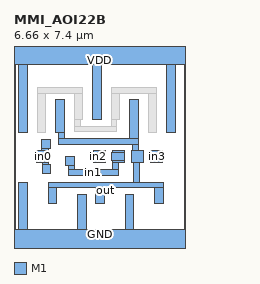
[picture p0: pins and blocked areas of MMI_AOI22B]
MACRO MMI_AOI22B
	CLASS CORE ;
	FOREIGN MMI_AOI22B 0 0 ;
	SIZE 6.66 BY 7.4 ;
	SYMMETRY X Y ;
	SITE CORE1 ;
	PIN out
		DIRECTION output ;
		USE SIGNAL ;
		PORT
			LAYER M1 ;
			RECT 1.62 4.275 1.96 5.555 ;
			LAYER M1 ;
			RECT 1.73 4.025 1.96 4.275 ;
			LAYER M1 ;
			RECT 4.5 4.025 4.84 5.555 ;
			LAYER M1 ;
			RECT 1.73 3.795 4.84 4.025 ;
			LAYER M1 ;
			RECT 4.61 3.555 4.84 3.795 ;
			LAYER M1 ;
			RECT 4.585 3.105 5.035 3.555 ;
			LAYER M1 ;
			RECT 4.655 2.335 4.885 3.105 ;
			LAYER M1 ;
			RECT 1.33 2.105 5.82 2.335 ;
			LAYER M1 ;
			RECT 1.33 1.495 1.67 2.105 ;
			LAYER M1 ;
			RECT 3.18 1.495 3.52 2.105 ;
			LAYER M1 ;
			RECT 5.48 1.495 5.82 2.105 ;
		END
		AntennaDiffArea 3.3672 ;
	END out
	PIN in1
		DIRECTION input ;
		USE SIGNAL ;
		PORT
			LAYER M1 ;
			RECT 3.845 3.5 4.295 3.555 ;
			LAYER M1 ;
			RECT 2 2.995 2.34 3.335 ;
			LAYER M1 ;
			RECT 3.785 3.16 4.295 3.5 ;
			LAYER M1 ;
			RECT 2.11 2.815 2.34 2.995 ;
			LAYER M1 ;
			RECT 3.835 3.105 4.295 3.16 ;
			LAYER M1 ;
			RECT 3.835 2.815 4.065 3.105 ;
			LAYER M1 ;
			RECT 2.11 2.585 4.065 2.815 ;
		END
		AntennaGateArea 0.9936 ;
	END in1
	PIN GND
		DIRECTION inout ;
		USE GROUND ;
		PORT
			LAYER M1 ;
			RECT 0.18 0.5 0.52 2.335 ;
			LAYER M1 ;
			RECT 2.48 0.5 2.82 1.835 ;
			LAYER M1 ;
			RECT 4.33 0.5 4.67 1.835 ;
			LAYER M1 ;
			RECT 0 -0.5 6.66 0.5 ;
		END
	END GND
	PIN in2
		DIRECTION input ;
		USE SIGNAL ;
		PORT
			LAYER M1 ;
			RECT 3.105 3.5 3.555 3.555 ;
			LAYER M1 ;
			RECT 3.015 3.16 3.555 3.5 ;
			LAYER M1 ;
			RECT 3.105 3.105 3.555 3.16 ;
		END
		AntennaGateArea 0.9936 ;
	END in2
	PIN VDD
		DIRECTION inout ;
		USE POWER ;
		PORT
			LAYER M1 ;
			RECT 0 6.9 6.66 7.9 ;
			LAYER M1 ;
			RECT 0.18 4.275 0.52 6.9 ;
			LAYER M1 ;
			RECT 3.06 4.755 3.4 6.9 ;
			LAYER M1 ;
			RECT 5.94 4.275 6.28 6.9 ;
		END
	END VDD
	PIN in3
		DIRECTION input ;
		USE SIGNAL ;
		PORT
			LAYER M1 ;
			RECT 5.325 3.105 5.775 3.555 ;
		END
		AntennaGateArea 0.9936 ;
	END in3
	PIN in0
		DIRECTION input ;
		USE SIGNAL ;
		PORT
			LAYER M1 ;
			RECT 1.09 3.65 1.43 3.99 ;
			LAYER M1 ;
			RECT 1.09 3.555 1.335 3.65 ;
			LAYER M1 ;
			RECT 0.885 3.105 1.335 3.555 ;
			LAYER M1 ;
			RECT 1.1 3 1.335 3.105 ;
			LAYER M1 ;
			RECT 1.1 2.66 1.44 3 ;
		END
		AntennaGateArea 0.9936 ;
	END in0
	OBS
		LAYER M1 ;
		RECT 0.9 6.02 1.24 6.035 ;
		LAYER M1 ;
		RECT 2.34 6.02 2.68 6.035 ;
		LAYER M1 ;
		RECT 0.9 5.79 2.68 6.02 ;
		LAYER M1 ;
		RECT 0.9 4.275 1.24 5.79 ;
		LAYER M1 ;
		RECT 2.34 4.755 2.68 5.79 ;
		LAYER M1 ;
		RECT 3.78 6.025 4.12 6.035 ;
		LAYER M1 ;
		RECT 5.22 6.025 5.56 6.035 ;
		LAYER M1 ;
		RECT 3.78 5.795 5.56 6.025 ;
		LAYER M1 ;
		RECT 3.78 4.755 4.12 5.795 ;
		LAYER M1 ;
		RECT 2.365 4.515 2.595 4.755 ;
		LAYER M1 ;
		RECT 3.78 4.515 4.01 4.755 ;
		LAYER M1 ;
		RECT 2.365 4.285 4.01 4.515 ;
		LAYER M1 ;
		RECT 5.22 4.275 5.56 5.795 ;
	END
END MMI_AOI22B
